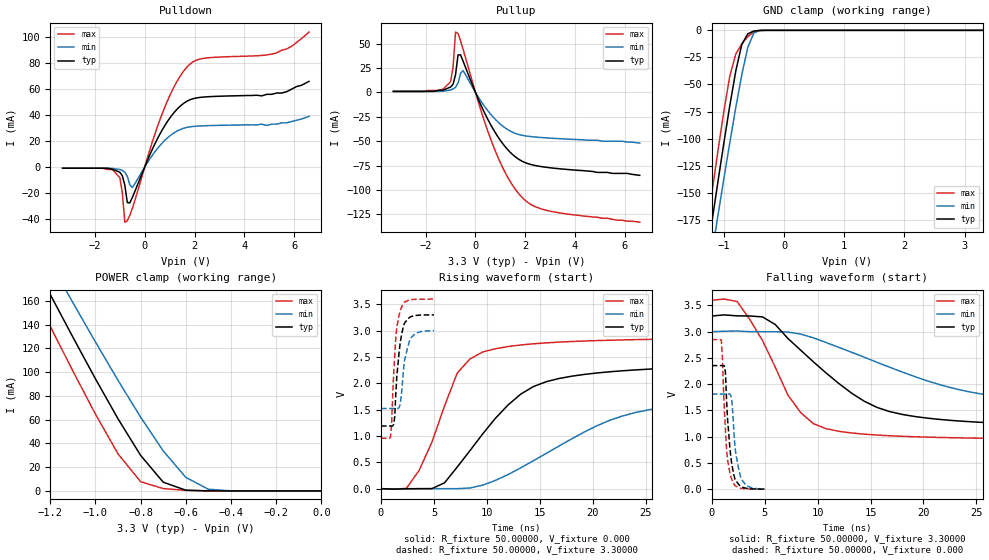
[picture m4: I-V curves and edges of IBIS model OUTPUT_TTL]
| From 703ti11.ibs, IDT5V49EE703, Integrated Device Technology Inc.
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|   Model OUTPUT_TTL
[Model]   OUTPUT_TTL
Model_type   3-state
Polarity   Non-Inverting
Enable   Active-High
Vmeas =  1.65000V
C_comp   7.85000pF   7.85000pF   7.85000pF
[Temperature Range]   25.00000   100.00000   -40.00000
[Voltage Range]   3.30000V   3.00000V   3.60000V
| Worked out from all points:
|   slope of the pulldown table from 0 to 0.495 V, typ, clamps not added: 23.4 ohm
|   slope of the pullup table from 0 to 0.495 V, typ, clamps not added: 18 ohm
|   GND clamp passes 1 mA (typ) near -0.51 V on its own axis
|   POWER clamp passes 1 mA (typ) near -0.61 V on its own axis
|   rising waveform, R_fixture 50.00000, V_fixture 0.000: 20-80 % time 6.52ns typ, 11.3ns min, 3.48ns max; typ from 0 V to 2.35 V
|   rising waveform, R_fixture 50.00000, V_fixture 3.30000: 20-80 % time 547ps typ, 604ps min, 451ps max; typ from 1.19 V to 3.3 V
|   falling waveform, R_fixture 50.00000, V_fixture 3.30000: 20-80 % time 7.9ns typ, 13.4ns min, 4.23ns max; typ from 3.3 V to 1.19 V
|   falling waveform, R_fixture 50.00000, V_fixture 0.000: 20-80 % time 536ps typ, 581ps min, 445ps max; typ from 2.35 V to 0.002 V
[Pulldown]
| voltage   I(typ)   I(min)   I(max)
-3.3V     -1mA       -1mA       -1mA
-1.3V     -1.8mA     -1.1mA     -2mA
-1V       -4.1mA     -2mA       -8.3mA
-900mV    -6.8mA     -2.7mA     -20.1mA
-800mV    -14.1mA    -4.1mA     -42.61mA
-700mV    -27.47mA   -7.2mA     -41.53mA
-600mV    -27.69mA   -13.78mA   -37.22mA
700mV     28.47mA    18.42mA    40.99mA
1.7V      50.72mA    30.51mA    77.06mA
2.3V      53.79mA    31.67mA    83.54mA
5.3V      57mA       33mA       88mA
6.6V      66mA       39mA       104mA
[Pullup]
| voltage   I(typ)   I(min)   I(max)
-3.3V     1mA        1mA        1mA
-1.3V     2.3mA      1.3mA      3.4mA
-1V       5.5mA      2.4mA      10.9mA
-900mV    8.3mA      3.7mA      25.9mA
-800mV    18.2mA     5.2mA      61.79mA
-700mV    38.4mA     9.6mA      60.42mA
-600mV    38.5mA     19.47mA    52.99mA
-500mV    32.24mA    22.32mA    44.42mA
700mV     -37.14mA   -25mA      -53.77mA
1.9V      -70.87mA   -44.11mA   -108.3mA
2.9V      -76.93mA   -46.71mA   -121.2mA
6.6V      -85mA      -52mA      -133mA
[GND_clamp]
| voltage   I(typ)   I(min)   I(max)
-3.3V     -992.9mA   -970.1mA   -1.017A
-1.3V     -215.6mA   -242.3mA   -191.1mA
-1.2V     -178mA     -207mA     -151.4mA
-1.1V     -140.9mA   -172mA     -112.5mA
-1V       -104.5mA   -137.5mA   -75.29mA
-900mV    -69.52mA   -103.7mA   -42.26mA
-800mV    -37.35mA   -71.1mA    -21.75mA
-700mV    -12.91mA   -40.75mA   -12.54mA
-600mV    -3.185mA   -15.58mA   -5.724mA
-500mV    -635.8uA   -2.421mA   -1.438mA
-400mV    -69.98uA   -165.2uA   -148uA
3.3V      688.9pA    4.084uA    187.4pA
[POWER_clamp]
| voltage   I(typ)   I(min)   I(max)
-3.3V     952mA      926.9mA    968.4mA
-1.3V     201.5mA    226mA      176.7mA
-1.2V     165.2mA    192mA      138.4mA
-1.1V     129.4mA    158.4mA    100.9mA
-1V       94.29mA    125.3mA    64.57mA
-900mV    60.64mA    93mA       31.15mA
-800mV    29.89mA    62.06mA    7.756mA
-700mV    7.344mA    33.66mA    1.97mA
-600mV    611uA      11.37mA    451.7uA
-500mV    56.05uA    1.412mA    58.07uA
-400mV    5.393uA    79.29uA    5.064uA
0V        688.9pA    3.732nA    251.1pA
[Ramp]
| variable   typ   min   max
dV/dt_r   1.41300/6.44776n   1.08780/11.26987n   1.71000/3.45127n
dV/dt_f   1.26660/7.85571n   0.88680/13.35733n   1.58664/4.33128n
R_load = 50.00000
[Rising Waveform]
R_fixture = 50.00000
V_fixture = 0.000
V_fixture_min = 0.000
V_fixture_max = 0.000
| time   V(typ)   V(min)   V(max)
0s        0V         0V         0V
2.4ns     -1.403mV   -5.824mV   5.377mV
3.6ns     -83.83uV   -648.6uV   346.8mV
6ns       110.7mV    -35.2uV    1.57V
7.2ns     410.7mV    -1.815uV   2.193V
10.8ns    1.334V     156mV      2.655V
15.6ns    2.03V      668.5mV    2.767V
21.6ns    2.218V     1.297V     2.817V
26.4ns    2.279V     1.534V     2.836V
60ns      2.355V     1.813V     2.85V
[Rising Waveform]
R_fixture = 50.00000
V_fixture = 3.30000
V_fixture_min = 3.00000
V_fixture_max = 3.60000
| time   V(typ)   V(min)   V(max)
0s        1.189V     1.521V     955.6mV
900ps     1.189V     1.521V     982.6mV
1ns       1.189V     1.521V     1.224V
1.2ns     1.22V      1.521V     2.203V
1.3ns     1.373V     1.521V     2.544V
1.4ns     1.809V     1.521V     2.873V
1.9ns     2.875V     1.733V     3.428V
2.2ns     3.131V     2.406V     3.537V
2.8ns     3.263V     2.854V     3.586V
5ns       3.298V     2.997V     3.598V
[Falling Waveform]
R_fixture = 50.00000
V_fixture = 3.30000
V_fixture_min = 3.00000
V_fixture_max = 3.60000
| time   V(typ)   V(min)   V(max)
0s        3.3V       3V         3.6V
2.4ns     3.302V     3.014V     3.575V
4.8ns     3.282V     3V         2.831V
7.2ns     2.871V     2.994V     1.791V
8.4ns     2.648V     2.954V     1.46V
10.8ns    2.215V     2.794V     1.153V
15.6ns    1.559V     2.418V     1.032V
20.4ns    1.353V     2.061V     991.7mV
33.6ns    1.214V     1.644V     956.6mV
60ns      1.189V     1.522V     955.6mV
[Falling Waveform]
R_fixture = 50.00000
V_fixture = 0.000
V_fixture_min = 0.000
V_fixture_max = 0.000
| time   V(typ)   V(min)   V(max)
0s        2.355V     1.813V     2.85V
900ps     2.355V     1.813V     2.842V
1ns       2.355V     1.813V     2.564V
1.2ns     2.349V     1.813V     1.482V
1.3ns     2.212V     1.813V     1.119V
1.4ns     1.704V     1.813V     762.9mV
1.9ns     473.2mV    1.687V     181.5mV
2.2ns     189.9mV    789.4mV    68.61mV
2.8ns     44.6mV     192.3mV    15.09mV
5ns       1.887mV    3.427mV    700uV
